VERSION 5.7 ;
  NOWIREEXTENSIONATPIN ON ;
  DIVIDERCHAR "/" ;
  BUSBITCHARS "[]" ;
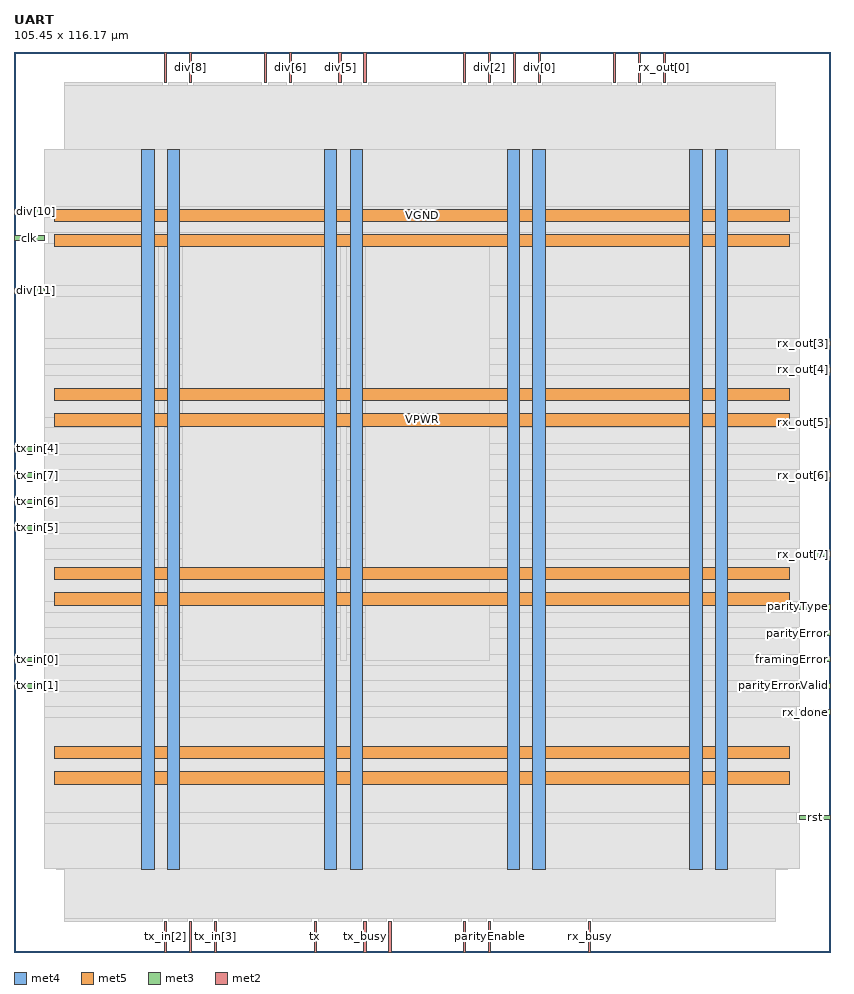
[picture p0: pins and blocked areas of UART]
MACRO UART
  CLASS BLOCK ;
  FOREIGN UART ;
  ORIGIN 0.000 0.000 ;
  SIZE 105.450 BY 116.170 ;
  PIN VGND
    DIRECTION INOUT ;
    USE GROUND ;
    PORT
      LAYER met4 ;
        RECT 19.805 10.640 21.405 103.600 ;
    END
    PORT
      LAYER met4 ;
        RECT 43.380 10.640 44.980 103.600 ;
    END
    PORT
      LAYER met4 ;
        RECT 66.955 10.640 68.555 103.600 ;
    END
    PORT
      LAYER met4 ;
        RECT 90.530 10.640 92.130 103.600 ;
    END
    PORT
      LAYER met5 ;
        RECT 5.280 24.940 100.060 26.540 ;
    END
    PORT
      LAYER met5 ;
        RECT 5.280 48.060 100.060 49.660 ;
    END
    PORT
      LAYER met5 ;
        RECT 5.280 71.180 100.060 72.780 ;
    END
    PORT
      LAYER met5 ;
        RECT 5.280 94.300 100.060 95.900 ;
    END
  END VGND
  PIN VPWR
    DIRECTION INOUT ;
    USE POWER ;
    PORT
      LAYER met4 ;
        RECT 16.505 10.640 18.105 103.600 ;
    END
    PORT
      LAYER met4 ;
        RECT 40.080 10.640 41.680 103.600 ;
    END
    PORT
      LAYER met4 ;
        RECT 63.655 10.640 65.255 103.600 ;
    END
    PORT
      LAYER met4 ;
        RECT 87.230 10.640 88.830 103.600 ;
    END
    PORT
      LAYER met5 ;
        RECT 5.280 21.640 100.060 23.240 ;
    END
    PORT
      LAYER met5 ;
        RECT 5.280 44.760 100.060 46.360 ;
    END
    PORT
      LAYER met5 ;
        RECT 5.280 67.880 100.060 69.480 ;
    END
    PORT
      LAYER met5 ;
        RECT 5.280 91.000 100.060 92.600 ;
    END
  END VPWR
  PIN clk
    DIRECTION INPUT ;
    USE SIGNAL ;
    ANTENNAGATEAREA 0.852000 ;
    ANTENNADIFFAREA 0.434700 ;
    PORT
      LAYER met3 ;
        RECT 0.000 91.840 4.000 92.440 ;
    END
  END clk
  PIN div[0]
    DIRECTION INPUT ;
    USE SIGNAL ;
    ANTENNAGATEAREA 0.196500 ;
    ANTENNADIFFAREA 0.434700 ;
    PORT
      LAYER met2 ;
        RECT 67.710 112.170 67.990 116.170 ;
    END
  END div[0]
  PIN div[10]
    DIRECTION INPUT ;
    USE SIGNAL ;
    ANTENNAGATEAREA 0.196500 ;
    ANTENNADIFFAREA 0.434700 ;
    PORT
      LAYER met3 ;
        RECT 0.000 95.240 4.000 95.840 ;
    END
  END div[10]
  PIN div[11]
    DIRECTION INPUT ;
    USE SIGNAL ;
    ANTENNAGATEAREA 0.196500 ;
    ANTENNADIFFAREA 0.434700 ;
    PORT
      LAYER met3 ;
        RECT 0.000 85.040 4.000 85.640 ;
    END
  END div[11]
  PIN div[1]
    DIRECTION INPUT ;
    USE SIGNAL ;
    ANTENNAGATEAREA 0.196500 ;
    ANTENNADIFFAREA 0.434700 ;
    PORT
      LAYER met2 ;
        RECT 64.490 112.170 64.770 116.170 ;
    END
  END div[1]
  PIN div[2]
    DIRECTION INPUT ;
    USE SIGNAL ;
    ANTENNAGATEAREA 0.196500 ;
    ANTENNADIFFAREA 0.434700 ;
    PORT
      LAYER met2 ;
        RECT 61.270 112.170 61.550 116.170 ;
    END
  END div[2]
  PIN div[3]
    DIRECTION INPUT ;
    USE SIGNAL ;
    ANTENNAGATEAREA 0.196500 ;
    ANTENNADIFFAREA 0.434700 ;
    PORT
      LAYER met2 ;
        RECT 58.050 112.170 58.330 116.170 ;
    END
  END div[3]
  PIN div[4]
    DIRECTION INPUT ;
    USE SIGNAL ;
    ANTENNAGATEAREA 0.196500 ;
    ANTENNADIFFAREA 0.434700 ;
    PORT
      LAYER met2 ;
        RECT 45.170 112.170 45.450 116.170 ;
    END
  END div[4]
  PIN div[5]
    DIRECTION INPUT ;
    USE SIGNAL ;
    ANTENNAGATEAREA 0.196500 ;
    ANTENNADIFFAREA 0.434700 ;
    PORT
      LAYER met2 ;
        RECT 41.950 112.170 42.230 116.170 ;
    END
  END div[5]
  PIN div[6]
    DIRECTION INPUT ;
    USE SIGNAL ;
    ANTENNAGATEAREA 0.196500 ;
    ANTENNADIFFAREA 0.434700 ;
    PORT
      LAYER met2 ;
        RECT 35.510 112.170 35.790 116.170 ;
    END
  END div[6]
  PIN div[7]
    DIRECTION INPUT ;
    USE SIGNAL ;
    ANTENNAGATEAREA 0.196500 ;
    ANTENNADIFFAREA 0.434700 ;
    PORT
      LAYER met2 ;
        RECT 32.290 112.170 32.570 116.170 ;
    END
  END div[7]
  PIN div[8]
    DIRECTION INPUT ;
    USE SIGNAL ;
    ANTENNAGATEAREA 0.196500 ;
    ANTENNADIFFAREA 0.434700 ;
    PORT
      LAYER met2 ;
        RECT 22.630 112.170 22.910 116.170 ;
    END
  END div[8]
  PIN div[9]
    DIRECTION INPUT ;
    USE SIGNAL ;
    ANTENNAGATEAREA 0.196500 ;
    ANTENNADIFFAREA 0.434700 ;
    PORT
      LAYER met2 ;
        RECT 19.410 112.170 19.690 116.170 ;
    END
  END div[9]
  PIN framingError
    DIRECTION OUTPUT ;
    USE SIGNAL ;
    ANTENNADIFFAREA 0.445500 ;
    PORT
      LAYER met3 ;
        RECT 101.450 37.440 105.450 38.040 ;
    END
  END framingError
  PIN parityEnable
    DIRECTION INPUT ;
    USE SIGNAL ;
    ANTENNAGATEAREA 0.126000 ;
    ANTENNADIFFAREA 0.434700 ;
    PORT
      LAYER met2 ;
        RECT 61.270 0.000 61.550 4.000 ;
    END
  END parityEnable
  PIN parityError
    DIRECTION OUTPUT ;
    USE SIGNAL ;
    ANTENNADIFFAREA 0.445500 ;
    PORT
      LAYER met3 ;
        RECT 101.450 40.840 105.450 41.440 ;
    END
  END parityError
  PIN parityErrorValid
    DIRECTION OUTPUT ;
    USE SIGNAL ;
    ANTENNADIFFAREA 0.445500 ;
    PORT
      LAYER met3 ;
        RECT 101.450 34.040 105.450 34.640 ;
    END
  END parityErrorValid
  PIN parityType
    DIRECTION INPUT ;
    USE SIGNAL ;
    ANTENNAGATEAREA 0.196500 ;
    ANTENNADIFFAREA 0.434700 ;
    PORT
      LAYER met3 ;
        RECT 101.450 44.240 105.450 44.840 ;
    END
  END parityType
  PIN rst
    DIRECTION INPUT ;
    USE SIGNAL ;
    ANTENNAGATEAREA 0.196500 ;
    ANTENNADIFFAREA 0.434700 ;
    PORT
      LAYER met3 ;
        RECT 101.450 17.040 105.450 17.640 ;
    END
  END rst
  PIN rx
    DIRECTION INPUT ;
    USE SIGNAL ;
    ANTENNAGATEAREA 0.196500 ;
    ANTENNADIFFAREA 0.434700 ;
    PORT
      LAYER met2 ;
        RECT 58.050 0.000 58.330 4.000 ;
    END
  END rx
  PIN rx_busy
    DIRECTION OUTPUT ;
    USE SIGNAL ;
    ANTENNADIFFAREA 0.445500 ;
    PORT
      LAYER met2 ;
        RECT 74.150 0.000 74.430 4.000 ;
    END
  END rx_busy
  PIN rx_done
    DIRECTION OUTPUT ;
    USE SIGNAL ;
    ANTENNADIFFAREA 0.445500 ;
    PORT
      LAYER met3 ;
        RECT 101.450 30.640 105.450 31.240 ;
    END
  END rx_done
  PIN rx_out[0]
    DIRECTION OUTPUT ;
    USE SIGNAL ;
    ANTENNADIFFAREA 0.795200 ;
    PORT
      LAYER met2 ;
        RECT 83.810 112.170 84.090 116.170 ;
    END
  END rx_out[0]
  PIN rx_out[1]
    DIRECTION OUTPUT ;
    USE SIGNAL ;
    ANTENNADIFFAREA 0.795200 ;
    PORT
      LAYER met2 ;
        RECT 80.590 112.170 80.870 116.170 ;
    END
  END rx_out[1]
  PIN rx_out[2]
    DIRECTION OUTPUT ;
    USE SIGNAL ;
    ANTENNADIFFAREA 0.795200 ;
    PORT
      LAYER met2 ;
        RECT 77.370 112.170 77.650 116.170 ;
    END
  END rx_out[2]
  PIN rx_out[3]
    DIRECTION OUTPUT ;
    USE SIGNAL ;
    ANTENNADIFFAREA 0.445500 ;
    PORT
      LAYER met3 ;
        RECT 101.450 78.240 105.450 78.840 ;
    END
  END rx_out[3]
  PIN rx_out[4]
    DIRECTION OUTPUT ;
    USE SIGNAL ;
    ANTENNADIFFAREA 0.445500 ;
    PORT
      LAYER met3 ;
        RECT 101.450 74.840 105.450 75.440 ;
    END
  END rx_out[4]
  PIN rx_out[5]
    DIRECTION OUTPUT ;
    USE SIGNAL ;
    ANTENNADIFFAREA 0.445500 ;
    PORT
      LAYER met3 ;
        RECT 101.450 68.040 105.450 68.640 ;
    END
  END rx_out[5]
  PIN rx_out[6]
    DIRECTION OUTPUT ;
    USE SIGNAL ;
    ANTENNADIFFAREA 0.445500 ;
    PORT
      LAYER met3 ;
        RECT 101.450 61.240 105.450 61.840 ;
    END
  END rx_out[6]
  PIN rx_out[7]
    DIRECTION OUTPUT ;
    USE SIGNAL ;
    ANTENNADIFFAREA 0.445500 ;
    PORT
      LAYER met3 ;
        RECT 101.450 51.040 105.450 51.640 ;
    END
  END rx_out[7]
  PIN tx
    DIRECTION OUTPUT ;
    USE SIGNAL ;
    ANTENNADIFFAREA 0.445500 ;
    PORT
      LAYER met2 ;
        RECT 38.730 0.000 39.010 4.000 ;
    END
  END tx
  PIN tx_busy
    DIRECTION OUTPUT ;
    USE SIGNAL ;
    ANTENNADIFFAREA 0.445500 ;
    PORT
      LAYER met2 ;
        RECT 45.170 0.000 45.450 4.000 ;
    END
  END tx_busy
  PIN tx_data_valid
    DIRECTION INPUT ;
    USE SIGNAL ;
    ANTENNAGATEAREA 0.159000 ;
    ANTENNADIFFAREA 0.434700 ;
    PORT
      LAYER met2 ;
        RECT 22.630 0.000 22.910 4.000 ;
    END
  END tx_data_valid
  PIN tx_done
    DIRECTION OUTPUT ;
    USE SIGNAL ;
    ANTENNADIFFAREA 0.445500 ;
    PORT
      LAYER met2 ;
        RECT 48.390 0.000 48.670 4.000 ;
    END
  END tx_done
  PIN tx_in[0]
    DIRECTION INPUT ;
    USE SIGNAL ;
    ANTENNAGATEAREA 0.196500 ;
    ANTENNADIFFAREA 0.434700 ;
    PORT
      LAYER met3 ;
        RECT 0.000 37.440 4.000 38.040 ;
    END
  END tx_in[0]
  PIN tx_in[1]
    DIRECTION INPUT ;
    USE SIGNAL ;
    ANTENNAGATEAREA 0.196500 ;
    ANTENNADIFFAREA 0.434700 ;
    PORT
      LAYER met3 ;
        RECT 0.000 34.040 4.000 34.640 ;
    END
  END tx_in[1]
  PIN tx_in[2]
    DIRECTION INPUT ;
    USE SIGNAL ;
    ANTENNAGATEAREA 0.196500 ;
    ANTENNADIFFAREA 0.434700 ;
    PORT
      LAYER met2 ;
        RECT 19.410 0.000 19.690 4.000 ;
    END
  END tx_in[2]
  PIN tx_in[3]
    DIRECTION INPUT ;
    USE SIGNAL ;
    ANTENNAGATEAREA 0.196500 ;
    ANTENNADIFFAREA 0.434700 ;
    PORT
      LAYER met2 ;
        RECT 25.850 0.000 26.130 4.000 ;
    END
  END tx_in[3]
  PIN tx_in[4]
    DIRECTION INPUT ;
    USE SIGNAL ;
    ANTENNAGATEAREA 0.196500 ;
    ANTENNADIFFAREA 0.434700 ;
    PORT
      LAYER met3 ;
        RECT 0.000 64.640 4.000 65.240 ;
    END
  END tx_in[4]
  PIN tx_in[5]
    DIRECTION INPUT ;
    USE SIGNAL ;
    ANTENNAGATEAREA 0.196500 ;
    ANTENNADIFFAREA 0.434700 ;
    PORT
      LAYER met3 ;
        RECT 0.000 54.440 4.000 55.040 ;
    END
  END tx_in[5]
  PIN tx_in[6]
    DIRECTION INPUT ;
    USE SIGNAL ;
    ANTENNAGATEAREA 0.196500 ;
    ANTENNADIFFAREA 0.434700 ;
    PORT
      LAYER met3 ;
        RECT 0.000 57.840 4.000 58.440 ;
    END
  END tx_in[6]
  PIN tx_in[7]
    DIRECTION INPUT ;
    USE SIGNAL ;
    ANTENNAGATEAREA 0.196500 ;
    ANTENNADIFFAREA 0.434700 ;
    PORT
      LAYER met3 ;
        RECT 0.000 61.240 4.000 61.840 ;
    END
  END tx_in[7]
  OBS
      LAYER nwell ;
        RECT 5.330 10.795 100.010 103.445 ;
      LAYER li1 ;
        RECT 5.520 10.795 99.820 103.445 ;
      LAYER met1 ;
        RECT 5.520 10.640 99.820 103.600 ;
      LAYER met2 ;
        RECT 6.530 111.890 19.130 112.170 ;
        RECT 19.970 111.890 22.350 112.170 ;
        RECT 23.190 111.890 32.010 112.170 ;
        RECT 32.850 111.890 35.230 112.170 ;
        RECT 36.070 111.890 41.670 112.170 ;
        RECT 42.510 111.890 44.890 112.170 ;
        RECT 45.730 111.890 57.770 112.170 ;
        RECT 58.610 111.890 60.990 112.170 ;
        RECT 61.830 111.890 64.210 112.170 ;
        RECT 65.050 111.890 67.430 112.170 ;
        RECT 68.270 111.890 77.090 112.170 ;
        RECT 77.930 111.890 80.310 112.170 ;
        RECT 81.150 111.890 83.530 112.170 ;
        RECT 84.370 111.890 98.350 112.170 ;
        RECT 6.530 4.280 98.350 111.890 ;
        RECT 6.530 4.000 19.130 4.280 ;
        RECT 19.970 4.000 22.350 4.280 ;
        RECT 23.190 4.000 25.570 4.280 ;
        RECT 26.410 4.000 38.450 4.280 ;
        RECT 39.290 4.000 44.890 4.280 ;
        RECT 45.730 4.000 48.110 4.280 ;
        RECT 48.950 4.000 57.770 4.280 ;
        RECT 58.610 4.000 60.990 4.280 ;
        RECT 61.830 4.000 73.870 4.280 ;
        RECT 74.710 4.000 98.350 4.280 ;
      LAYER met3 ;
        RECT 4.000 96.240 101.450 103.525 ;
        RECT 4.400 94.840 101.450 96.240 ;
        RECT 4.000 92.840 101.450 94.840 ;
        RECT 4.400 91.440 101.450 92.840 ;
        RECT 4.000 86.040 101.450 91.440 ;
        RECT 4.400 84.640 101.450 86.040 ;
        RECT 4.000 79.240 101.450 84.640 ;
        RECT 4.000 77.840 101.050 79.240 ;
        RECT 4.000 75.840 101.450 77.840 ;
        RECT 4.000 74.440 101.050 75.840 ;
        RECT 4.000 69.040 101.450 74.440 ;
        RECT 4.000 67.640 101.050 69.040 ;
        RECT 4.000 65.640 101.450 67.640 ;
        RECT 4.400 64.240 101.450 65.640 ;
        RECT 4.000 62.240 101.450 64.240 ;
        RECT 4.400 60.840 101.050 62.240 ;
        RECT 4.000 58.840 101.450 60.840 ;
        RECT 4.400 57.440 101.450 58.840 ;
        RECT 4.000 55.440 101.450 57.440 ;
        RECT 4.400 54.040 101.450 55.440 ;
        RECT 4.000 52.040 101.450 54.040 ;
        RECT 4.000 50.640 101.050 52.040 ;
        RECT 4.000 45.240 101.450 50.640 ;
        RECT 4.000 43.840 101.050 45.240 ;
        RECT 4.000 41.840 101.450 43.840 ;
        RECT 4.000 40.440 101.050 41.840 ;
        RECT 4.000 38.440 101.450 40.440 ;
        RECT 4.400 37.040 101.050 38.440 ;
        RECT 4.000 35.040 101.450 37.040 ;
        RECT 4.400 33.640 101.050 35.040 ;
        RECT 4.000 31.640 101.450 33.640 ;
        RECT 4.000 30.240 101.050 31.640 ;
        RECT 4.000 18.040 101.450 30.240 ;
        RECT 4.000 16.640 101.050 18.040 ;
        RECT 4.000 10.715 101.450 16.640 ;
      LAYER met4 ;
        RECT 18.695 37.575 19.405 92.305 ;
        RECT 21.805 37.575 39.680 92.305 ;
        RECT 42.080 37.575 42.980 92.305 ;
        RECT 45.380 37.575 61.345 92.305 ;
  END
END UART
END LIBRARY

